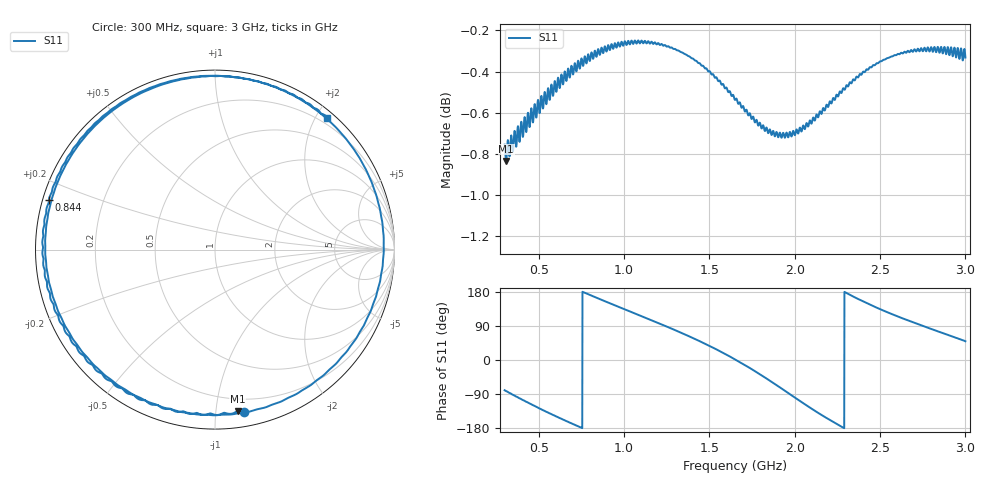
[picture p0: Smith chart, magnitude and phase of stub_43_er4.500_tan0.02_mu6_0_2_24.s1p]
! Chirptenna · simulación 3D de un stub abierto
# HZ S RI R 50
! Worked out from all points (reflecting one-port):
!   2001 points, 300 MHz to 3 GHz, reference 50 ohm
!   lowest |S11| = -0.8 dB at 309.4 MHz (marker M1), VSWR 20.82, Z = 5.56 - j57.2 ohm
!   phase of S11 starts at -80 deg and turns -591 deg over the sweep
!   S11 on the Smith chart (normalised r, x): 300 MHz: 0.11, -1.19; 844 MHz: 0.02, +0.15; 3 GHz: 0.11, +2.17
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3e8  0.1633 -0.902
3.0945e8  0.1262 -0.8995
3.864e8  -0.173 -0.902
4.6335e8  -0.4481 -0.8144
5.4705e8  -0.6866 -0.6405
6.375e8  -0.8713 -0.3811
7.401e8  -0.955 -0.0539
8.4405e8  -0.9253 0.2757
9.75e8  -0.7308 0.6354
1.15185e9  -0.2769 0.9297
1.3125e9  0.2309 0.9384
1.39215e9  0.4775 0.8355
1.4718e9  0.6944 0.6583
1.569e9  0.8823 0.3476
1.65e9  0.9395 0.0287
1.72695e9  0.884 -0.295
1.80255e9  0.713 -0.5904
1.90245e9  0.328 -0.8601
1.9875e9  -0.0794 -0.9195
2.07255e9  -0.4739 -0.7971
2.16165e9  -0.7769 -0.5186
2.2386e9  -0.9166 -0.2121
2.325e9  -0.9392 0.1382
2.406e9  -0.8538 0.4274
2.49375e9  -0.6838 0.6736
2.6625e9  -0.2436 0.9349
2.8272e9  0.2105 0.9423
3e9  0.6259 0.7312
